! (c) 2009  Infineon Technologies AG, Munich
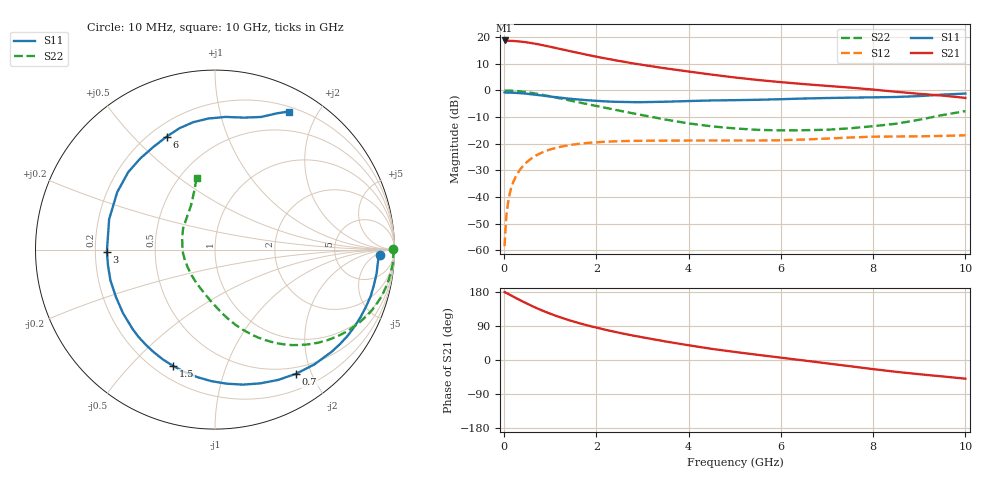
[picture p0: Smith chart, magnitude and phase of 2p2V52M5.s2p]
! Infineon Technologies  Discrete & RF Semiconductors
! BFP420
! VCE =  2.5 V,  IC =  2.5 mA
! Common Emitter S-Parameters:  Nov 2009
# GHz  S  MA  R  50
!  f  S11  S21  S12  S22
! GHz  MAG  ANG  MAG  ANG  MAG  ANG  MAG  ANG
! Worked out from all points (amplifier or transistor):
!   46 points, 10 MHz to 10 GHz, reference 50 ohm
!   highest |S21| = 18.7 dB at 10 MHz (marker M1)
!   |S21| within 3 dB of that: start of sweep to 1.164 GHz
!   unconditionally stable (mu >= 1): 3.717 GHz to end of sweep
!   at 300 MHz: K = 0.05, MSG = 24.6 dB, |S12| = -30.9 dB
!   at 1.7 GHz: K = 0.39, MSG = 16.8 dB, |S12| = -19.9 dB
!   at 10 GHz: K = 1.19, MAG = 4.3 dB, |S12| = -16.8 dB
!   lowest NFmin = 0.55 dB at 900 MHz
!   S11 on the Smith chart (normalised r, x): 10 MHz: 21, -8; 700 MHz: 0.41, -1.77; 1.5 GHz: 0.27, -0.67; 3 GHz: 0.25, -0.01; 6 GHz: 0.26, +0.63; 10 GHz: 0.25, +1.64
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0.01  0.9193 -1.8  8.647 179.2  0.0012 55.8  0.9932 0.1
0.02  0.9129 -1.6  8.43 178.9  0.0019 87.5  0.994 -0.9
0.05  0.9106 -4.1  8.471 176.7  0.0047 85.6  0.994 -2.3
0.15  0.9073 -12.5  8.487 170.4  0.0146 83.1  0.9886 -7.2
0.3  0.8937 -25.0  8.326 160.8  0.0286 76.2  0.9687 -14.2
0.45  0.8727 -37.2  8.054 151.6  0.0418 69.3  0.9378 -21.0
0.6  0.8462 -49.1  7.699 142.7  0.0537 62.9  0.8979 -27.4
0.7  0.8261 -56.9  7.44 137.2  0.0608 58.9  0.8681 -31.4
1  0.7678 -78.4  6.58 122.2  0.0782 48.2  0.774 -42.1
1.2  0.7328 -91.7  6.025 113.3  0.0869 42.1  0.7121 -48.3
1.5  0.6891 -109.8  5.287 101.8  0.0966 34.4  0.6275 -56.3
1.7  0.6655 -120.9  4.859 94.8  0.1013 30.0  0.5773 -60.9
2.2  0.6228 -145.5  3.977 79.7  0.1091 20.9  0.4712 -71.0
2.6  0.6076 -163.4  3.439 69.2  0.1123 15.0  0.4008 -78.4
3  0.6027 -178.9  3.011 59.9  0.1137 10.5  0.3432 -85.4
3.5  0.6136 164.0  2.591 48.9  0.1143 5.8  0.2842 -95.4
4.5  0.6482 138.2  1.979 29.4  0.1148 -0.5  0.212 -119.7
5.5  0.6672 120.9  1.569 13.6  0.115 -4.1  0.1822 -145.4
6  0.6846 113.2  1.429 6.2  0.1164 -5.0  0.1778 -159.7
7  0.7201 99.7  1.217 -8.9  0.125 -7.6  0.1829 173.4
8.5  0.7529 77.6  0.942 -31.2  0.1368 -16.9  0.2375 131.5
10  0.8722 61.9  0.724 -49.3  0.144 -22.7  0.4094 104.5
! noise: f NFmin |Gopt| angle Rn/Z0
0.9  0.55  0.41  33  0.2
1.8  1.02  0.24  78  0.16
2.4  1.11  0.26  103  0.15
3  1.28  0.27  140  0.11
4  1.5  0.34  -163  0.1
5  1.85  0.4  -130  0.26
6  2.56  0.5  -109  0.35
